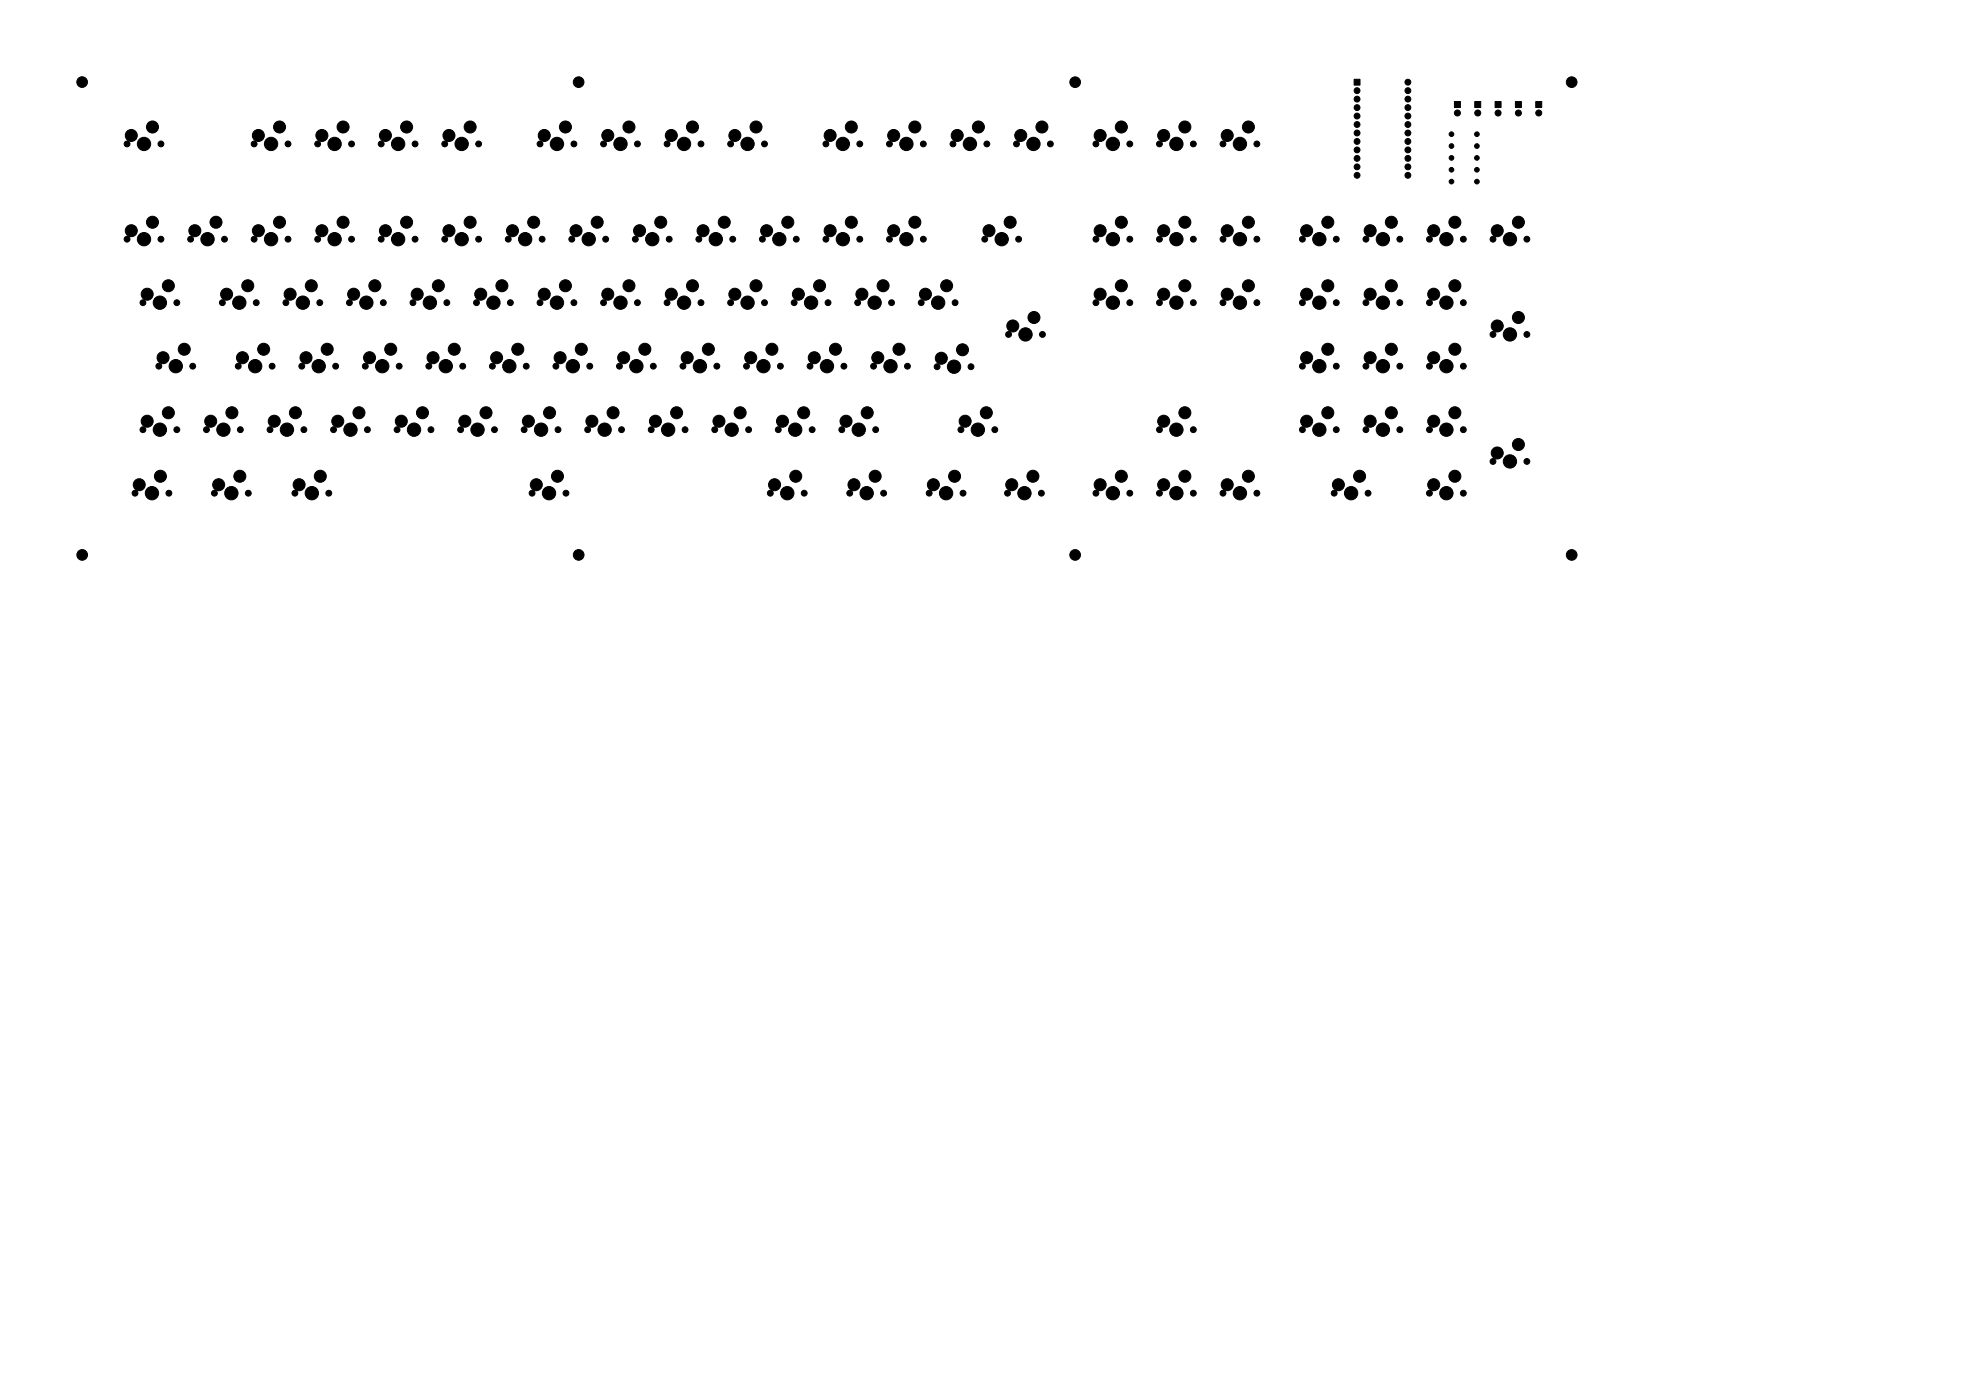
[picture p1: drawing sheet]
<svg xmlns="http://www.w3.org/2000/svg" width="594mm" height="420mm" viewBox="0 0 594 420" stroke-linecap="round" stroke-linejoin="round" font-family="sans-serif">
<g fill="#000" stroke="#000" stroke-width=".3">
<path d="M406 23.8h1.8v1.7h-1.8zM436.1 30.5h1.8v1.8h-1.8zM442.2 30.5h1.8v1.8h-1.8zM448.3 30.5h1.8v1.8h-1.8zM454.4 30.5h1.8v1.8h-1.8zM460.5 30.5h1.8v1.8h-1.8z"/>
<circle cx="24.6" cy="24.6" r="1.6"/>
<circle cx="45.7" cy="38.1" r="1.8"/>
<circle cx="83.8" cy="38.1" r="1.8"/>
<circle cx="102.9" cy="38.1" r="1.8"/>
<circle cx="121.9" cy="38.1" r="1.8"/>
<circle cx="141" cy="38.1" r="1.8"/>
<circle cx="169.5" cy="38.1" r="1.8"/>
<circle cx="173.5" cy="24.6" r="1.6"/>
<circle cx="188.6" cy="38.1" r="1.8"/>
<circle cx="207.6" cy="38.1" r="1.8"/>
<circle cx="226.7" cy="38.1" r="1.8"/>
<circle cx="255.3" cy="38.1" r="1.8"/>
<circle cx="274.3" cy="38.1" r="1.8"/>
<circle cx="293.4" cy="38.1" r="1.8"/>
<circle cx="312.4" cy="38.1" r="1.8"/>
<circle cx="322.4" cy="24.7" r="1.6"/>
<circle cx="336.2" cy="38.1" r="1.8"/>
<circle cx="355.3" cy="38.1" r="1.8"/>
<circle cx="374.3" cy="38.1" r="1.8"/>
<circle cx="406.9" cy="39.9" r=".88"/>
<circle cx="406.9" cy="34.8" r=".88"/>
<circle cx="406.9" cy="27.2" r=".88"/>
<circle cx="406.9" cy="29.7" r=".88"/>
<circle cx="406.9" cy="32.3" r=".88"/>
<circle cx="406.9" cy="37.4" r=".88"/>
<circle cx="422.2" cy="32.3" r=".88"/>
<circle cx="422.2" cy="27.2" r=".88"/>
<circle cx="422.2" cy="39.9" r=".88"/>
<circle cx="422.2" cy="37.4" r=".88"/>
<circle cx="422.2" cy="24.7" r=".88"/>
<circle cx="422.2" cy="34.8" r=".88"/>
<circle cx="422.2" cy="29.7" r=".88"/>
<circle cx="437" cy="33.9" r=".9"/>
<circle cx="443.1" cy="33.9" r=".9"/>
<circle cx="449.2" cy="33.9" r=".9"/>
<circle cx="455.3" cy="33.9" r=".9"/>
<circle cx="461.4" cy="33.9" r=".9"/>
<circle cx="471.3" cy="24.6" r="1.6"/>
<circle cx="38.1" cy="43.2" r=".87"/>
<circle cx="39.4" cy="40.6" r="1.8"/>
<circle cx="43.2" cy="43.2" r="2"/>
<circle cx="48.3" cy="43.2" r=".87"/>
<circle cx="76.2" cy="43.2" r=".87"/>
<circle cx="77.5" cy="40.6" r="1.8"/>
<circle cx="81.3" cy="43.2" r="2"/>
<circle cx="86.4" cy="43.2" r=".87"/>
<circle cx="95.2" cy="43.2" r=".87"/>
<circle cx="96.5" cy="40.6" r="1.8"/>
<circle cx="100.3" cy="43.2" r="2"/>
<circle cx="105.4" cy="43.2" r=".87"/>
<circle cx="114.3" cy="43.2" r=".87"/>
<circle cx="115.6" cy="40.6" r="1.8"/>
<circle cx="119.4" cy="43.2" r="2"/>
<circle cx="124.5" cy="43.2" r=".87"/>
<circle cx="133.3" cy="43.2" r=".87"/>
<circle cx="134.6" cy="40.6" r="1.8"/>
<circle cx="138.4" cy="43.2" r="2"/>
<circle cx="143.5" cy="43.2" r=".87"/>
<circle cx="161.9" cy="43.2" r=".87"/>
<circle cx="163.2" cy="40.6" r="1.8"/>
<circle cx="167" cy="43.2" r="2"/>
<circle cx="172.1" cy="43.2" r=".87"/>
<circle cx="181" cy="43.2" r=".87"/>
<circle cx="182.2" cy="40.6" r="1.8"/>
<circle cx="186.1" cy="43.2" r="2"/>
<circle cx="191.1" cy="43.2" r=".87"/>
<circle cx="200" cy="43.2" r=".87"/>
<circle cx="201.3" cy="40.6" r="1.8"/>
<circle cx="205.1" cy="43.2" r="2"/>
<circle cx="210.2" cy="43.2" r=".87"/>
<circle cx="219.1" cy="43.2" r=".87"/>
<circle cx="220.3" cy="40.6" r="1.8"/>
<circle cx="224.2" cy="43.2" r="2"/>
<circle cx="229.2" cy="43.2" r=".87"/>
<circle cx="247.6" cy="43.2" r=".87"/>
<circle cx="248.9" cy="40.6" r="1.8"/>
<circle cx="252.7" cy="43.2" r="2"/>
<circle cx="257.8" cy="43.2" r=".87"/>
<circle cx="266.7" cy="43.2" r=".87"/>
<circle cx="268" cy="40.6" r="1.8"/>
<circle cx="271.8" cy="43.2" r="2"/>
<circle cx="276.9" cy="43.2" r=".87"/>
<circle cx="285.8" cy="43.2" r=".87"/>
<circle cx="287" cy="40.6" r="1.8"/>
<circle cx="290.8" cy="43.2" r="2"/>
<circle cx="295.9" cy="43.2" r=".87"/>
<circle cx="304.8" cy="43.2" r=".87"/>
<circle cx="306.1" cy="40.6" r="1.8"/>
<circle cx="309.9" cy="43.2" r="2"/>
<circle cx="315" cy="43.2" r=".87"/>
<circle cx="328.6" cy="43.2" r=".87"/>
<circle cx="329.9" cy="40.6" r="1.8"/>
<circle cx="333.7" cy="43.2" r="2"/>
<circle cx="338.8" cy="43.2" r=".87"/>
<circle cx="347.7" cy="43.2" r=".87"/>
<circle cx="348.9" cy="40.6" r="1.8"/>
<circle cx="352.7" cy="43.2" r="2"/>
<circle cx="357.8" cy="43.2" r=".87"/>
<circle cx="366.7" cy="43.2" r=".87"/>
<circle cx="368" cy="40.6" r="1.8"/>
<circle cx="371.8" cy="43.2" r="2"/>
<circle cx="376.9" cy="43.2" r=".87"/>
<circle cx="406.9" cy="45" r=".88"/>
<circle cx="406.9" cy="50.1" r=".88"/>
<circle cx="406.9" cy="47.5" r=".88"/>
<circle cx="406.9" cy="52.6" r=".88"/>
<circle cx="406.9" cy="42.4" r=".88"/>
<circle cx="422.2" cy="42.4" r=".88"/>
<circle cx="422.2" cy="52.6" r=".88"/>
<circle cx="422.2" cy="47.5" r=".88"/>
<circle cx="422.2" cy="50.1" r=".88"/>
<circle cx="422.2" cy="45" r=".88"/>
<circle cx="435.2" cy="43.8" r=".7"/>
<circle cx="435.2" cy="54.5" r=".7"/>
<circle cx="435.2" cy="40.3" r=".7"/>
<circle cx="435.2" cy="50.9" r=".7"/>
<circle cx="435.2" cy="47.4" r=".7"/>
<circle cx="442.8" cy="50.9" r=".7"/>
<circle cx="442.8" cy="54.5" r=".7"/>
<circle cx="442.8" cy="40.3" r=".7"/>
<circle cx="442.8" cy="47.4" r=".7"/>
<circle cx="442.8" cy="43.8" r=".7"/>
<circle cx="38.1" cy="71.8" r=".87"/>
<circle cx="39.4" cy="69.2" r="1.8"/>
<circle cx="43.2" cy="71.8" r="2"/>
<circle cx="45.7" cy="66.7" r="1.8"/>
<circle cx="48.3" cy="71.8" r=".87"/>
<circle cx="57.1" cy="71.8" r=".87"/>
<circle cx="58.4" cy="69.2" r="1.8"/>
<circle cx="62.2" cy="71.8" r="2"/>
<circle cx="64.8" cy="66.7" r="1.8"/>
<circle cx="67.3" cy="71.8" r=".87"/>
<circle cx="76.2" cy="71.8" r=".87"/>
<circle cx="77.5" cy="69.2" r="1.8"/>
<circle cx="81.3" cy="71.8" r="2"/>
<circle cx="83.8" cy="66.7" r="1.8"/>
<circle cx="86.4" cy="71.8" r=".87"/>
<circle cx="95.2" cy="71.8" r=".87"/>
<circle cx="96.5" cy="69.2" r="1.8"/>
<circle cx="100.3" cy="71.8" r="2"/>
<circle cx="102.9" cy="66.7" r="1.8"/>
<circle cx="105.4" cy="71.8" r=".87"/>
<circle cx="114.3" cy="71.8" r=".87"/>
<circle cx="115.6" cy="69.2" r="1.8"/>
<circle cx="119.4" cy="71.8" r="2"/>
<circle cx="121.9" cy="66.7" r="1.8"/>
<circle cx="124.5" cy="71.8" r=".87"/>
<circle cx="133.3" cy="71.8" r=".87"/>
<circle cx="134.6" cy="69.2" r="1.8"/>
<circle cx="138.4" cy="71.8" r="2"/>
<circle cx="141" cy="66.7" r="1.8"/>
<circle cx="143.5" cy="71.8" r=".87"/>
<circle cx="152.4" cy="71.8" r=".87"/>
<circle cx="153.7" cy="69.2" r="1.8"/>
<circle cx="157.5" cy="71.8" r="2"/>
<circle cx="160" cy="66.7" r="1.8"/>
<circle cx="162.6" cy="71.8" r=".87"/>
<circle cx="171.4" cy="71.8" r=".87"/>
<circle cx="172.7" cy="69.2" r="1.8"/>
<circle cx="176.5" cy="71.8" r="2"/>
<circle cx="179.1" cy="66.7" r="1.8"/>
<circle cx="181.6" cy="71.8" r=".87"/>
<circle cx="190.5" cy="71.8" r=".87"/>
<circle cx="191.8" cy="69.2" r="1.8"/>
<circle cx="195.6" cy="71.8" r="2"/>
<circle cx="198.1" cy="66.7" r="1.8"/>
<circle cx="200.7" cy="71.8" r=".87"/>
<circle cx="209.5" cy="71.8" r=".87"/>
<circle cx="210.8" cy="69.2" r="1.8"/>
<circle cx="214.6" cy="71.8" r="2"/>
<circle cx="217.2" cy="66.7" r="1.8"/>
<circle cx="219.7" cy="71.8" r=".87"/>
<circle cx="228.6" cy="71.8" r=".87"/>
<circle cx="229.9" cy="69.2" r="1.8"/>
<circle cx="233.7" cy="71.8" r="2"/>
<circle cx="236.2" cy="66.7" r="1.8"/>
<circle cx="238.8" cy="71.8" r=".87"/>
<circle cx="247.6" cy="71.8" r=".87"/>
<circle cx="248.9" cy="69.2" r="1.8"/>
<circle cx="252.7" cy="71.8" r="2"/>
<circle cx="255.3" cy="66.7" r="1.8"/>
<circle cx="257.8" cy="71.8" r=".87"/>
<circle cx="266.7" cy="71.8" r=".87"/>
<circle cx="268" cy="69.2" r="1.8"/>
<circle cx="271.8" cy="71.8" r="2"/>
<circle cx="274.3" cy="66.7" r="1.8"/>
<circle cx="276.9" cy="71.8" r=".87"/>
<circle cx="295.3" cy="71.8" r=".87"/>
<circle cx="296.5" cy="69.2" r="1.8"/>
<circle cx="300.4" cy="71.8" r="2"/>
<circle cx="302.9" cy="66.7" r="1.8"/>
<circle cx="305.4" cy="71.8" r=".87"/>
<circle cx="328.6" cy="71.8" r=".87"/>
<circle cx="329.9" cy="69.2" r="1.8"/>
<circle cx="333.7" cy="71.8" r="2"/>
<circle cx="336.2" cy="66.7" r="1.8"/>
<circle cx="338.8" cy="71.8" r=".87"/>
<circle cx="347.7" cy="71.8" r=".87"/>
<circle cx="348.9" cy="69.2" r="1.8"/>
<circle cx="352.7" cy="71.8" r="2"/>
<circle cx="355.3" cy="66.7" r="1.8"/>
<circle cx="357.8" cy="71.8" r=".87"/>
<circle cx="366.7" cy="71.8" r=".87"/>
<circle cx="368" cy="69.2" r="1.8"/>
<circle cx="371.8" cy="71.8" r="2"/>
<circle cx="374.3" cy="66.7" r="1.8"/>
<circle cx="376.9" cy="71.8" r=".87"/>
<circle cx="390.5" cy="71.8" r=".87"/>
<circle cx="391.8" cy="69.2" r="1.8"/>
<circle cx="395.6" cy="71.8" r="2"/>
<circle cx="398.1" cy="66.7" r="1.8"/>
<circle cx="400.7" cy="71.8" r=".87"/>
<circle cx="409.6" cy="71.8" r=".87"/>
<circle cx="410.8" cy="69.2" r="1.8"/>
<circle cx="414.7" cy="71.8" r="2"/>
<circle cx="417.2" cy="66.7" r="1.8"/>
<circle cx="419.7" cy="71.8" r=".87"/>
<circle cx="428.6" cy="71.8" r=".87"/>
<circle cx="429.9" cy="69.2" r="1.8"/>
<circle cx="433.7" cy="71.8" r="2"/>
<circle cx="436.2" cy="66.7" r="1.8"/>
<circle cx="438.8" cy="71.8" r=".87"/>
<circle cx="447.7" cy="71.8" r=".87"/>
<circle cx="448.9" cy="69.2" r="1.8"/>
<circle cx="452.8" cy="71.8" r="2"/>
<circle cx="455.3" cy="66.7" r="1.8"/>
<circle cx="457.8" cy="71.8" r=".87"/>
<circle cx="42.9" cy="90.8" r=".87"/>
<circle cx="44.1" cy="88.3" r="1.8"/>
<circle cx="47.9" cy="90.8" r="2"/>
<circle cx="50.5" cy="85.7" r="1.8"/>
<circle cx="53" cy="90.8" r=".87"/>
<circle cx="66.7" cy="90.8" r=".87"/>
<circle cx="67.9" cy="88.3" r="1.8"/>
<circle cx="71.8" cy="90.8" r="2"/>
<circle cx="74.3" cy="85.7" r="1.8"/>
<circle cx="76.8" cy="90.8" r=".87"/>
<circle cx="85.7" cy="90.8" r=".87"/>
<circle cx="87" cy="88.3" r="1.8"/>
<circle cx="90.8" cy="90.8" r="2"/>
<circle cx="93.3" cy="85.7" r="1.8"/>
<circle cx="95.9" cy="90.8" r=".87"/>
<circle cx="104.8" cy="90.8" r=".87"/>
<circle cx="106" cy="88.3" r="1.8"/>
<circle cx="109.9" cy="90.8" r="2"/>
<circle cx="112.4" cy="85.7" r="1.8"/>
<circle cx="114.9" cy="90.8" r=".87"/>
<circle cx="123.8" cy="90.8" r=".87"/>
<circle cx="125.1" cy="88.3" r="1.8"/>
<circle cx="128.9" cy="90.8" r="2"/>
<circle cx="131.4" cy="85.7" r="1.8"/>
<circle cx="134" cy="90.8" r=".87"/>
<circle cx="142.9" cy="90.8" r=".87"/>
<circle cx="144.1" cy="88.3" r="1.8"/>
<circle cx="148" cy="90.8" r="2"/>
<circle cx="150.5" cy="85.7" r="1.8"/>
<circle cx="153" cy="90.8" r=".87"/>
<circle cx="161.9" cy="90.8" r=".87"/>
<circle cx="163.2" cy="88.3" r="1.8"/>
<circle cx="167" cy="90.8" r="2"/>
<circle cx="169.5" cy="85.7" r="1.8"/>
<circle cx="172.1" cy="90.8" r=".87"/>
<circle cx="181" cy="90.8" r=".87"/>
<circle cx="182.2" cy="88.3" r="1.8"/>
<circle cx="186.1" cy="90.8" r="2"/>
<circle cx="188.6" cy="85.7" r="1.8"/>
<circle cx="191.1" cy="90.8" r=".87"/>
<circle cx="200" cy="90.8" r=".87"/>
<circle cx="201.3" cy="88.3" r="1.8"/>
<circle cx="205.1" cy="90.8" r="2"/>
<circle cx="207.6" cy="85.7" r="1.8"/>
<circle cx="210.2" cy="90.8" r=".87"/>
<circle cx="219.1" cy="90.8" r=".87"/>
<circle cx="220.3" cy="88.3" r="1.8"/>
<circle cx="224.2" cy="90.8" r="2"/>
<circle cx="226.7" cy="85.7" r="1.8"/>
<circle cx="229.2" cy="90.8" r=".87"/>
<circle cx="238.1" cy="90.8" r=".87"/>
<circle cx="239.4" cy="88.3" r="1.8"/>
<circle cx="243.2" cy="90.8" r="2"/>
<circle cx="245.7" cy="85.7" r="1.8"/>
<circle cx="248.3" cy="90.8" r=".87"/>
<circle cx="257.2" cy="90.8" r=".87"/>
<circle cx="258.4" cy="88.3" r="1.8"/>
<circle cx="262.3" cy="90.8" r="2"/>
<circle cx="264.8" cy="85.7" r="1.8"/>
<circle cx="267.3" cy="90.8" r=".87"/>
<circle cx="276.2" cy="90.8" r=".87"/>
<circle cx="277.5" cy="88.3" r="1.8"/>
<circle cx="281.3" cy="90.8" r="2"/>
<circle cx="283.8" cy="85.7" r="1.8"/>
<circle cx="286.4" cy="90.8" r=".87"/>
<circle cx="303.7" cy="97.8" r="1.8"/>
<circle cx="310" cy="95.3" r="1.8"/>
<circle cx="328.6" cy="90.8" r=".87"/>
<circle cx="329.9" cy="88.3" r="1.8"/>
<circle cx="333.7" cy="90.8" r="2"/>
<circle cx="336.2" cy="85.7" r="1.8"/>
<circle cx="338.8" cy="90.8" r=".87"/>
<circle cx="347.7" cy="90.8" r=".87"/>
<circle cx="348.9" cy="88.3" r="1.8"/>
<circle cx="352.7" cy="90.8" r="2"/>
<circle cx="355.3" cy="85.7" r="1.8"/>
<circle cx="357.8" cy="90.8" r=".87"/>
<circle cx="366.7" cy="90.8" r=".87"/>
<circle cx="368" cy="88.3" r="1.8"/>
<circle cx="371.8" cy="90.8" r="2"/>
<circle cx="374.3" cy="85.7" r="1.8"/>
<circle cx="376.9" cy="90.8" r=".87"/>
<circle cx="390.5" cy="90.8" r=".87"/>
<circle cx="391.8" cy="88.3" r="1.8"/>
<circle cx="395.6" cy="90.8" r="2"/>
<circle cx="398.1" cy="85.7" r="1.8"/>
<circle cx="400.7" cy="90.8" r=".87"/>
<circle cx="409.6" cy="90.8" r=".87"/>
<circle cx="410.8" cy="88.3" r="1.8"/>
<circle cx="414.7" cy="90.8" r="2"/>
<circle cx="417.2" cy="85.7" r="1.8"/>
<circle cx="419.7" cy="90.8" r=".87"/>
<circle cx="428.6" cy="90.8" r=".87"/>
<circle cx="429.9" cy="88.3" r="1.8"/>
<circle cx="433.7" cy="90.8" r="2"/>
<circle cx="436.2" cy="85.7" r="1.8"/>
<circle cx="438.8" cy="90.8" r=".87"/>
<circle cx="448.9" cy="97.8" r="1.8"/>
<circle cx="455.3" cy="95.3" r="1.8"/>
<circle cx="47.6" cy="109.9" r=".87"/>
<circle cx="48.9" cy="107.3" r="1.8"/>
<circle cx="52.7" cy="109.9" r="2"/>
<circle cx="55.2" cy="104.8" r="1.8"/>
<circle cx="57.8" cy="109.9" r=".87"/>
<circle cx="71.4" cy="109.9" r=".87"/>
<circle cx="72.7" cy="107.3" r="1.8"/>
<circle cx="76.5" cy="109.9" r="2"/>
<circle cx="79.1" cy="104.8" r="1.8"/>
<circle cx="81.6" cy="109.9" r=".87"/>
<circle cx="90.5" cy="109.9" r=".87"/>
<circle cx="91.8" cy="107.3" r="1.8"/>
<circle cx="95.6" cy="109.9" r="2"/>
<circle cx="98.1" cy="104.8" r="1.8"/>
<circle cx="100.6" cy="109.9" r=".87"/>
<circle cx="109.5" cy="109.9" r=".87"/>
<circle cx="110.8" cy="107.3" r="1.8"/>
<circle cx="114.6" cy="109.9" r="2"/>
<circle cx="117.2" cy="104.8" r="1.8"/>
<circle cx="119.7" cy="109.9" r=".87"/>
<circle cx="128.6" cy="109.9" r=".87"/>
<circle cx="129.9" cy="107.3" r="1.8"/>
<circle cx="133.7" cy="109.9" r="2"/>
<circle cx="136.2" cy="104.8" r="1.8"/>
<circle cx="138.7" cy="109.9" r=".87"/>
<circle cx="147.6" cy="109.9" r=".87"/>
<circle cx="148.9" cy="107.3" r="1.8"/>
<circle cx="152.7" cy="109.9" r="2"/>
<circle cx="155.3" cy="104.8" r="1.8"/>
<circle cx="157.8" cy="109.9" r=".87"/>
<circle cx="166.7" cy="109.9" r=".87"/>
<circle cx="168" cy="107.3" r="1.8"/>
<circle cx="171.8" cy="109.9" r="2"/>
<circle cx="174.3" cy="104.8" r="1.8"/>
<circle cx="176.8" cy="109.9" r=".87"/>
<circle cx="185.7" cy="109.9" r=".87"/>
<circle cx="187" cy="107.3" r="1.8"/>
<circle cx="190.8" cy="109.9" r="2"/>
<circle cx="193.4" cy="104.8" r="1.8"/>
<circle cx="195.9" cy="109.9" r=".87"/>
<circle cx="204.8" cy="109.9" r=".87"/>
<circle cx="206.1" cy="107.3" r="1.8"/>
<circle cx="209.9" cy="109.9" r="2"/>
<circle cx="212.4" cy="104.8" r="1.8"/>
<circle cx="214.9" cy="109.9" r=".87"/>
<circle cx="223.8" cy="109.9" r=".87"/>
<circle cx="225.1" cy="107.3" r="1.8"/>
<circle cx="228.9" cy="109.9" r="2"/>
<circle cx="231.5" cy="104.8" r="1.8"/>
<circle cx="234" cy="109.9" r=".87"/>
<circle cx="242.9" cy="109.9" r=".87"/>
<circle cx="244.2" cy="107.3" r="1.8"/>
<circle cx="248" cy="109.9" r="2"/>
<circle cx="250.5" cy="104.8" r="1.8"/>
<circle cx="253" cy="109.9" r=".87"/>
<circle cx="261.9" cy="109.9" r=".87"/>
<circle cx="263.2" cy="107.3" r="1.8"/>
<circle cx="267" cy="109.9" r="2"/>
<circle cx="269.6" cy="104.8" r="1.8"/>
<circle cx="272.1" cy="109.9" r=".87"/>
<circle cx="281" cy="110" r=".87"/>
<circle cx="282.3" cy="107.5" r="1.8"/>
<circle cx="286.1" cy="110" r="2"/>
<circle cx="288.6" cy="104.9" r="1.8"/>
<circle cx="291.1" cy="110" r=".87"/>
<circle cx="302.4" cy="100.3" r=".87"/>
<circle cx="307.5" cy="100.3" r="2"/>
<circle cx="312.6" cy="100.3" r=".87"/>
<circle cx="390.5" cy="109.9" r=".87"/>
<circle cx="391.8" cy="107.3" r="1.8"/>
<circle cx="395.6" cy="109.9" r="2"/>
<circle cx="398.1" cy="104.8" r="1.8"/>
<circle cx="400.7" cy="109.9" r=".87"/>
<circle cx="409.6" cy="109.9" r=".87"/>
<circle cx="410.8" cy="107.3" r="1.8"/>
<circle cx="414.7" cy="109.9" r="2"/>
<circle cx="417.2" cy="104.8" r="1.8"/>
<circle cx="419.7" cy="109.9" r=".87"/>
<circle cx="428.6" cy="109.9" r=".87"/>
<circle cx="429.9" cy="107.3" r="1.8"/>
<circle cx="433.7" cy="109.9" r="2"/>
<circle cx="436.2" cy="104.8" r="1.8"/>
<circle cx="438.8" cy="109.9" r=".87"/>
<circle cx="447.7" cy="100.3" r=".87"/>
<circle cx="452.8" cy="100.3" r="2"/>
<circle cx="457.8" cy="100.3" r=".87"/>
<circle cx="42.9" cy="128.9" r=".87"/>
<circle cx="44.1" cy="126.4" r="1.8"/>
<circle cx="47.9" cy="128.9" r="2"/>
<circle cx="50.5" cy="123.8" r="1.8"/>
<circle cx="53" cy="128.9" r=".87"/>
<circle cx="61.9" cy="128.9" r=".87"/>
<circle cx="63.2" cy="126.4" r="1.8"/>
<circle cx="67" cy="128.9" r="2"/>
<circle cx="69.5" cy="123.8" r="1.8"/>
<circle cx="72.1" cy="128.9" r=".87"/>
<circle cx="81" cy="128.9" r=".87"/>
<circle cx="82.2" cy="126.4" r="1.8"/>
<circle cx="86" cy="128.9" r="2"/>
<circle cx="88.6" cy="123.8" r="1.8"/>
<circle cx="91.1" cy="128.9" r=".87"/>
<circle cx="100" cy="128.9" r=".87"/>
<circle cx="101.3" cy="126.4" r="1.8"/>
<circle cx="105.1" cy="128.9" r="2"/>
<circle cx="107.6" cy="123.8" r="1.8"/>
<circle cx="110.2" cy="128.9" r=".87"/>
<circle cx="119.1" cy="128.9" r=".87"/>
<circle cx="120.3" cy="126.4" r="1.8"/>
<circle cx="124.1" cy="128.9" r="2"/>
<circle cx="126.7" cy="123.8" r="1.8"/>
<circle cx="129.2" cy="128.9" r=".87"/>
<circle cx="138.1" cy="128.9" r=".87"/>
<circle cx="139.4" cy="126.4" r="1.8"/>
<circle cx="143.2" cy="128.9" r="2"/>
<circle cx="145.7" cy="123.8" r="1.8"/>
<circle cx="148.3" cy="128.9" r=".87"/>
<circle cx="157.2" cy="128.9" r=".87"/>
<circle cx="158.4" cy="126.4" r="1.8"/>
<circle cx="162.2" cy="128.9" r="2"/>
<circle cx="164.8" cy="123.8" r="1.8"/>
<circle cx="167.3" cy="128.9" r=".87"/>
<circle cx="176.2" cy="128.9" r=".87"/>
<circle cx="177.5" cy="126.4" r="1.8"/>
<circle cx="181.3" cy="128.9" r="2"/>
<circle cx="183.8" cy="123.8" r="1.8"/>
<circle cx="186.4" cy="128.9" r=".87"/>
<circle cx="195.3" cy="128.9" r=".87"/>
<circle cx="196.5" cy="126.4" r="1.8"/>
<circle cx="200.3" cy="128.9" r="2"/>
<circle cx="202.9" cy="123.8" r="1.8"/>
<circle cx="205.4" cy="128.9" r=".87"/>
<circle cx="214.3" cy="128.9" r=".87"/>
<circle cx="215.6" cy="126.4" r="1.8"/>
<circle cx="219.4" cy="128.9" r="2"/>
<circle cx="221.9" cy="123.8" r="1.8"/>
<circle cx="224.5" cy="128.9" r=".87"/>
<circle cx="233.4" cy="128.9" r=".87"/>
<circle cx="234.6" cy="126.4" r="1.8"/>
<circle cx="238.4" cy="128.9" r="2"/>
<circle cx="241" cy="123.8" r="1.8"/>
<circle cx="243.5" cy="128.9" r=".87"/>
<circle cx="252.4" cy="128.9" r=".87"/>
<circle cx="253.7" cy="126.4" r="1.8"/>
<circle cx="257.5" cy="128.9" r="2"/>
<circle cx="260" cy="123.8" r="1.8"/>
<circle cx="262.6" cy="128.9" r=".87"/>
<circle cx="288.1" cy="128.9" r=".87"/>
<circle cx="289.4" cy="126.4" r="1.8"/>
<circle cx="293.2" cy="128.9" r="2"/>
<circle cx="295.8" cy="123.8" r="1.8"/>
<circle cx="298.3" cy="128.9" r=".87"/>
<circle cx="347.7" cy="128.9" r=".87"/>
<circle cx="348.9" cy="126.4" r="1.8"/>
<circle cx="352.7" cy="128.9" r="2"/>
<circle cx="355.3" cy="123.8" r="1.8"/>
<circle cx="357.8" cy="128.9" r=".87"/>
<circle cx="390.5" cy="128.9" r=".87"/>
<circle cx="391.8" cy="126.4" r="1.8"/>
<circle cx="395.6" cy="128.9" r="2"/>
<circle cx="398.1" cy="123.8" r="1.8"/>
<circle cx="400.7" cy="128.9" r=".87"/>
<circle cx="409.6" cy="128.9" r=".87"/>
<circle cx="410.8" cy="126.4" r="1.8"/>
<circle cx="414.7" cy="128.9" r="2"/>
<circle cx="417.2" cy="123.8" r="1.8"/>
<circle cx="419.7" cy="128.9" r=".87"/>
<circle cx="428.6" cy="128.9" r=".87"/>
<circle cx="429.9" cy="126.4" r="1.8"/>
<circle cx="433.7" cy="128.9" r="2"/>
<circle cx="436.2" cy="123.8" r="1.8"/>
<circle cx="438.8" cy="128.9" r=".87"/>
<circle cx="447.7" cy="138.4" r=".87"/>
<circle cx="448.9" cy="135.9" r="1.8"/>
<circle cx="452.8" cy="138.4" r="2"/>
<circle cx="455.3" cy="133.4" r="1.8"/>
<circle cx="457.8" cy="138.4" r=".87"/>
<circle cx="40.5" cy="148" r=".87"/>
<circle cx="41.8" cy="145.4" r="1.8"/>
<circle cx="45.6" cy="148" r="2"/>
<circle cx="48.1" cy="142.9" r="1.8"/>
<circle cx="50.6" cy="148" r=".87"/>
<circle cx="64.3" cy="148" r=".87"/>
<circle cx="65.6" cy="145.4" r="1.8"/>
<circle cx="69.4" cy="148" r="2"/>
<circle cx="71.9" cy="142.9" r="1.8"/>
<circle cx="74.5" cy="148" r=".87"/>
<circle cx="88.4" cy="148" r=".87"/>
<circle cx="89.7" cy="145.4" r="1.8"/>
<circle cx="93.5" cy="148" r="2"/>
<circle cx="96" cy="142.9" r="1.8"/>
<circle cx="98.6" cy="148" r=".87"/>
<circle cx="159.5" cy="148" r=".87"/>
<circle cx="160.8" cy="145.4" r="1.8"/>
<circle cx="164.6" cy="148" r="2"/>
<circle cx="167.2" cy="142.9" r="1.8"/>
<circle cx="169.7" cy="148" r=".87"/>
<circle cx="231" cy="148" r=".87"/>
<circle cx="232.3" cy="145.4" r="1.8"/>
<circle cx="236.1" cy="148" r="2"/>
<circle cx="238.6" cy="142.9" r="1.8"/>
<circle cx="241.1" cy="148" r=".87"/>
<circle cx="254.8" cy="148" r=".87"/>
<circle cx="256.1" cy="145.4" r="1.8"/>
<circle cx="259.9" cy="148" r="2"/>
<circle cx="262.4" cy="142.9" r="1.8"/>
<circle cx="265" cy="148" r=".87"/>
<circle cx="278.6" cy="148" r=".87"/>
<circle cx="279.9" cy="145.4" r="1.8"/>
<circle cx="283.7" cy="148" r="2"/>
<circle cx="286.2" cy="142.9" r="1.8"/>
<circle cx="288.8" cy="148" r=".87"/>
<circle cx="302.1" cy="148" r=".87"/>
<circle cx="303.4" cy="145.4" r="1.8"/>
<circle cx="307.2" cy="148" r="2"/>
<circle cx="309.7" cy="142.9" r="1.8"/>
<circle cx="312.3" cy="148" r=".87"/>
<circle cx="328.6" cy="148" r=".87"/>
<circle cx="329.9" cy="145.4" r="1.8"/>
<circle cx="333.7" cy="148" r="2"/>
<circle cx="336.2" cy="142.9" r="1.8"/>
<circle cx="338.8" cy="148" r=".87"/>
<circle cx="347.7" cy="148" r=".87"/>
<circle cx="348.9" cy="145.4" r="1.8"/>
<circle cx="352.7" cy="148" r="2"/>
<circle cx="355.3" cy="142.9" r="1.8"/>
<circle cx="357.8" cy="148" r=".87"/>
<circle cx="366.7" cy="148" r=".87"/>
<circle cx="368" cy="145.4" r="1.8"/>
<circle cx="371.8" cy="148" r="2"/>
<circle cx="374.3" cy="142.9" r="1.8"/>
<circle cx="376.9" cy="148" r=".87"/>
<circle cx="400.1" cy="148" r=".87"/>
<circle cx="401.3" cy="145.4" r="1.8"/>
<circle cx="405.1" cy="148" r="2"/>
<circle cx="407.7" cy="142.9" r="1.8"/>
<circle cx="410.2" cy="148" r=".87"/>
<circle cx="428.6" cy="148" r=".87"/>
<circle cx="429.9" cy="145.4" r="1.8"/>
<circle cx="433.7" cy="148" r="2"/>
<circle cx="436.2" cy="142.9" r="1.8"/>
<circle cx="438.8" cy="148" r=".87"/>
<circle cx="24.6" cy="166.5" r="1.6"/>
<circle cx="173.5" cy="166.5" r="1.6"/>
<circle cx="322.4" cy="166.5" r="1.6"/>
<circle cx="471.3" cy="166.5" r="1.6"/>
</g>
</svg>
